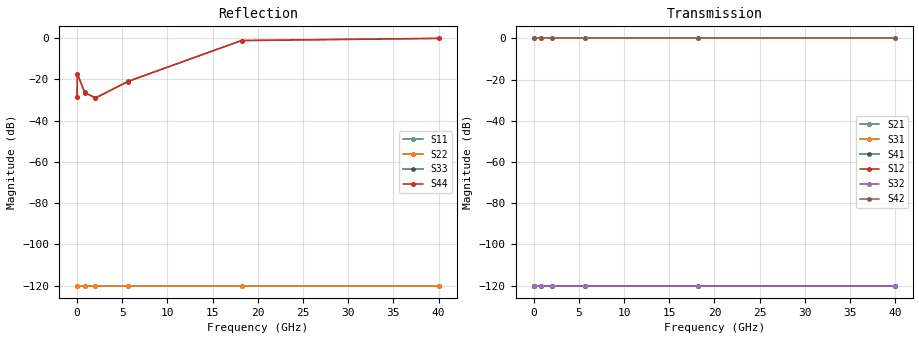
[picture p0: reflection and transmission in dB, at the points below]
! Copyright 2015, Texas Instruments Incorporated. All rights reserved.
! Generated by program util_convert_s2p_term_to_s4p on 03-13-2017 11:06:01
!  1 ----xxxxxxxxxxxxxxxxxx---- 3
!  xxxxxxxxxxxxxxxxxx
!  (Input) xxxxxxxxxxxxxxxxxx  (Output) <--- Termination looking in to TX
!  xxxxxxxxxxxxxxxxxx
!  2 ----xxxxxxxxxxxxxxxxxx---- 4
! FREQ  S11  S12  S13  S14
!  S21  S22  S23  S24
!  S31  S32  S33  S34
!  S41  S42  S43  S44
!  DB  ANG  DB  ANG  DB  ANG  DB  ANG
# HZ S DB R 50.00
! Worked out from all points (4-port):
!   461 points, 1 MHz to 40 GHz, reference 50 ohm
!   strongest paths, dB at 1 MHz, 14.13 MHz, 199.5 MHz, 2.818 GHz, 40 GHz:
!     S42: 0.0, 0.0, 0.0, 0.0, 0.0
!     S31: 0.0, 0.0, 0.0, 0.0, 0.0
!     S43: -43.8, -21.5, -17.7, -29.1, -83.4
!     S41: -120.0, -120.0, -120.0, -120.0, -120.0
!     S32: -120.0, -120.0, -120.0, -120.0, -120.0
!     S21: -120.0, -120.0, -120.0, -120.0, -120.0
!   lowest |S11| = -120.0 dB at 1 MHz (marker M1), VSWR 1.00, Z = 50 + j0 ohm
!   |S11| at or under -10 dB: start of sweep to end of sweep
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1000000  -120.00 0.0  -120.00 0.0  -120.00 0.0  -120.00 0.0
         -120.00 0.0  -120.00 0.0  -120.00 0.0  -120.00 0.0
         0.00 0.0  -120.00 0.0  -28.29 -164.1  -43.75 79.9
         -120.00 0.0  0.00 0.0  -43.75 79.9  -28.29 -164.1
5.01187e7  -120.00 0.0  -120.00 0.0  -120.00 0.0  -120.00 0.0
           -120.00 0.0  -120.00 0.0  -120.00 0.0  -120.00 0.0
           0.00 0.0  -120.00 0.0  -17.33 16.2  -15.26 12.3
           -120.00 0.0  0.00 0.0  -15.26 12.4  -17.33 16.3
8.51138e8  -120.00 0.0  -120.00 0.0  -120.00 0.0  -120.00 0.0
           -120.00 0.0  -120.00 0.0  -120.00 0.0  -120.00 0.0
           0.00 0.0  -120.00 0.0  -26.24 -95.7  -22.34 -69.1
           -120.00 0.0  0.00 0.0  -22.35 -68.7  -26.40 -95.0
2.04174e9  -120.00 0.0  -120.00 0.0  -120.00 0.0  -120.00 0.0
           -120.00 0.0  -120.00 0.0  -120.00 0.0  -120.00 0.0
           0.00 0.0  -120.00 0.0  -28.98 119.1  -49.44 -56.2
           -120.00 0.0  0.00 0.0  -47.76 -48.7  -29.03 116.1
5.62341e9  -120.00 0.0  -120.00 0.0  -120.00 0.0  -120.00 0.0
           -120.00 0.0  -120.00 0.0  -120.00 0.0  -120.00 0.0
           0.00 0.0  -120.00 0.0  -20.90 142.0  -19.15 -105.8
           -120.00 0.0  0.00 0.0  -18.92 -107.9  -21.04 146.8
1.8197e10  -120.00 0.0  -120.00 0.0  -120.00 0.0  -120.00 0.0
           -120.00 0.0  -120.00 0.0  -120.00 0.0  -120.00 0.0
           0.00 0.0  -120.00 0.0  -1.12 -8.5  -41.07 -40.3
           -120.00 0.0  0.00 0.0  -41.46 -40.0  -1.13 -8.4
4e10  -120.00 0.0  -120.00 0.0  -120.00 0.0  -120.00 0.0
      -120.00 0.0  -120.00 0.0  -120.00 0.0  -120.00 0.0
      0.00 0.0  -120.00 0.0  -0.07 -92.6  -83.02 1.6
      -120.00 0.0  0.00 0.0  -83.44 1.5  -0.07 -92.6
